VERSION 5.8 ;
BUSBITCHARS "[]" ;
DIVIDERCHAR "/" ;
UNITS
    DATABASE MICRONS 1000 ;
END UNITS

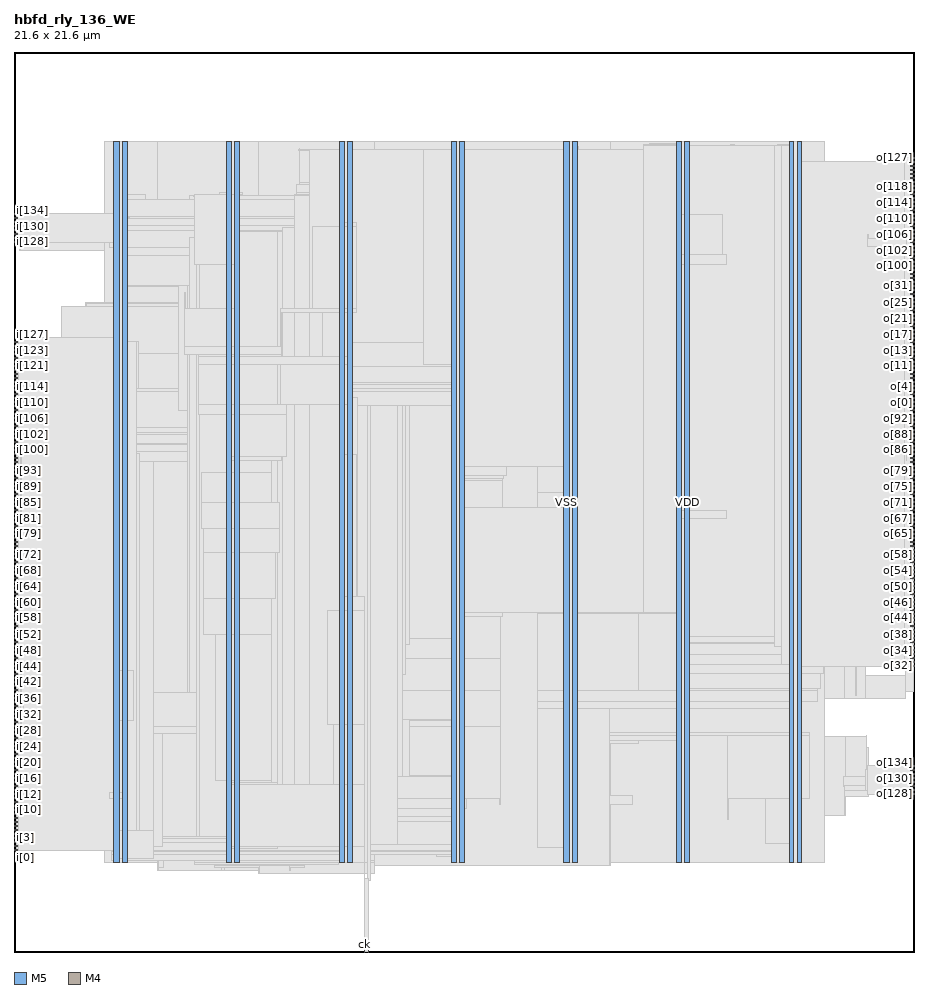
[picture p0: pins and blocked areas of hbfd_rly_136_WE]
MACRO hbfd_rly_136_WE
  FOREIGN hbfd_rly_136_WE 0 0 ;
  CLASS BLOCK ;
  SIZE 21.6 BY 21.6 ;
  PIN ck
    DIRECTION INPUT ;
    USE SIGNAL ;
    PORT
      LAYER M5 ;
        RECT  8.4 0 8.424 0.084 ;
    END
  END ck
  PIN i[0]
    DIRECTION INPUT ;
    USE SIGNAL ;
    PORT
      LAYER M4 ;
        RECT  0 2.448 0.084 2.472 ;
    END
  END i[0]
  PIN i[100]
    DIRECTION INPUT ;
    USE SIGNAL ;
    PORT
      LAYER M4 ;
        RECT  0 12.048 0.084 12.072 ;
    END
  END i[100]
  PIN i[101]
    DIRECTION INPUT ;
    USE SIGNAL ;
    PORT
      LAYER M4 ;
        RECT  0 12.144 0.084 12.168 ;
    END
  END i[101]
  PIN i[102]
    DIRECTION INPUT ;
    USE SIGNAL ;
    PORT
      LAYER M4 ;
        RECT  0 12.24 0.084 12.264 ;
    END
  END i[102]
  PIN i[103]
    DIRECTION INPUT ;
    USE SIGNAL ;
    PORT
      LAYER M4 ;
        RECT  0 12.336 0.084 12.36 ;
    END
  END i[103]
  PIN i[104]
    DIRECTION INPUT ;
    USE SIGNAL ;
    PORT
      LAYER M4 ;
        RECT  0 12.432 0.084 12.456 ;
    END
  END i[104]
  PIN i[105]
    DIRECTION INPUT ;
    USE SIGNAL ;
    PORT
      LAYER M4 ;
        RECT  0 12.528 0.084 12.552 ;
    END
  END i[105]
  PIN i[106]
    DIRECTION INPUT ;
    USE SIGNAL ;
    PORT
      LAYER M4 ;
        RECT  0 12.624 0.084 12.648 ;
    END
  END i[106]
  PIN i[107]
    DIRECTION INPUT ;
    USE SIGNAL ;
    PORT
      LAYER M4 ;
        RECT  0 12.72 0.084 12.744 ;
    END
  END i[107]
  PIN i[108]
    DIRECTION INPUT ;
    USE SIGNAL ;
    PORT
      LAYER M4 ;
        RECT  0 12.816 0.084 12.84 ;
    END
  END i[108]
  PIN i[109]
    DIRECTION INPUT ;
    USE SIGNAL ;
    PORT
      LAYER M4 ;
        RECT  0 12.912 0.084 12.936 ;
    END
  END i[109]
  PIN i[10]
    DIRECTION INPUT ;
    USE SIGNAL ;
    PORT
      LAYER M4 ;
        RECT  0 3.408 0.084 3.432 ;
    END
  END i[10]
  PIN i[110]
    DIRECTION INPUT ;
    USE SIGNAL ;
    PORT
      LAYER M4 ;
        RECT  0 13.008 0.084 13.032 ;
    END
  END i[110]
  PIN i[111]
    DIRECTION INPUT ;
    USE SIGNAL ;
    PORT
      LAYER M4 ;
        RECT  0 13.104 0.084 13.128 ;
    END
  END i[111]
  PIN i[112]
    DIRECTION INPUT ;
    USE SIGNAL ;
    PORT
      LAYER M4 ;
        RECT  0 13.2 0.084 13.224 ;
    END
  END i[112]
  PIN i[113]
    DIRECTION INPUT ;
    USE SIGNAL ;
    PORT
      LAYER M4 ;
        RECT  0 13.296 0.084 13.32 ;
    END
  END i[113]
  PIN i[114]
    DIRECTION INPUT ;
    USE SIGNAL ;
    PORT
      LAYER M4 ;
        RECT  0 13.392 0.084 13.416 ;
    END
  END i[114]
  PIN i[115]
    DIRECTION INPUT ;
    USE SIGNAL ;
    PORT
      LAYER M4 ;
        RECT  0 13.488 0.084 13.512 ;
    END
  END i[115]
  PIN i[116]
    DIRECTION INPUT ;
    USE SIGNAL ;
    PORT
      LAYER M4 ;
        RECT  0 13.584 0.084 13.608 ;
    END
  END i[116]
  PIN i[117]
    DIRECTION INPUT ;
    USE SIGNAL ;
    PORT
      LAYER M4 ;
        RECT  0 13.68 0.084 13.704 ;
    END
  END i[117]
  PIN i[118]
    DIRECTION INPUT ;
    USE SIGNAL ;
    PORT
      LAYER M4 ;
        RECT  0 13.776 0.084 13.8 ;
    END
  END i[118]
  PIN i[119]
    DIRECTION INPUT ;
    USE SIGNAL ;
    PORT
      LAYER M4 ;
        RECT  0 13.872 0.084 13.896 ;
    END
  END i[119]
  PIN i[11]
    DIRECTION INPUT ;
    USE SIGNAL ;
    PORT
      LAYER M4 ;
        RECT  0 3.504 0.084 3.528 ;
    END
  END i[11]
  PIN i[120]
    DIRECTION INPUT ;
    USE SIGNAL ;
    PORT
      LAYER M4 ;
        RECT  0 13.968 0.084 13.992 ;
    END
  END i[120]
  PIN i[121]
    DIRECTION INPUT ;
    USE SIGNAL ;
    PORT
      LAYER M4 ;
        RECT  0 14.064 0.084 14.088 ;
    END
  END i[121]
  PIN i[122]
    DIRECTION INPUT ;
    USE SIGNAL ;
    PORT
      LAYER M4 ;
        RECT  0 14.16 0.084 14.184 ;
    END
  END i[122]
  PIN i[123]
    DIRECTION INPUT ;
    USE SIGNAL ;
    PORT
      LAYER M4 ;
        RECT  0 14.256 0.084 14.28 ;
    END
  END i[123]
  PIN i[124]
    DIRECTION INPUT ;
    USE SIGNAL ;
    PORT
      LAYER M4 ;
        RECT  0 14.352 0.084 14.376 ;
    END
  END i[124]
  PIN i[125]
    DIRECTION INPUT ;
    USE SIGNAL ;
    PORT
      LAYER M4 ;
        RECT  0 14.448 0.084 14.472 ;
    END
  END i[125]
  PIN i[126]
    DIRECTION INPUT ;
    USE SIGNAL ;
    PORT
      LAYER M4 ;
        RECT  0 14.544 0.084 14.568 ;
    END
  END i[126]
  PIN i[127]
    DIRECTION INPUT ;
    USE SIGNAL ;
    PORT
      LAYER M4 ;
        RECT  0 14.64 0.084 14.664 ;
    END
  END i[127]
  PIN i[128]
    DIRECTION INPUT ;
    USE SIGNAL ;
    PORT
      LAYER M4 ;
        RECT  0 17.04 0.084 17.064 ;
    END
  END i[128]
  PIN i[129]
    DIRECTION INPUT ;
    USE SIGNAL ;
    PORT
      LAYER M4 ;
        RECT  0 17.136 0.084 17.16 ;
    END
  END i[129]
  PIN i[12]
    DIRECTION INPUT ;
    USE SIGNAL ;
    PORT
      LAYER M4 ;
        RECT  0 3.6 0.084 3.624 ;
    END
  END i[12]
  PIN i[130]
    DIRECTION INPUT ;
    USE SIGNAL ;
    PORT
      LAYER M4 ;
        RECT  0 17.232 0.084 17.256 ;
    END
  END i[130]
  PIN i[131]
    DIRECTION INPUT ;
    USE SIGNAL ;
    PORT
      LAYER M4 ;
        RECT  0 17.328 0.084 17.352 ;
    END
  END i[131]
  PIN i[132]
    DIRECTION INPUT ;
    USE SIGNAL ;
    PORT
      LAYER M4 ;
        RECT  0 17.424 0.084 17.448 ;
    END
  END i[132]
  PIN i[133]
    DIRECTION INPUT ;
    USE SIGNAL ;
    PORT
      LAYER M4 ;
        RECT  0 17.52 0.084 17.544 ;
    END
  END i[133]
  PIN i[134]
    DIRECTION INPUT ;
    USE SIGNAL ;
    PORT
      LAYER M4 ;
        RECT  0 17.616 0.084 17.64 ;
    END
  END i[134]
  PIN i[135]
    DIRECTION INPUT ;
    USE SIGNAL ;
    PORT
      LAYER M4 ;
        RECT  0 17.712 0.084 17.736 ;
    END
  END i[135]
  PIN i[13]
    DIRECTION INPUT ;
    USE SIGNAL ;
    PORT
      LAYER M4 ;
        RECT  0 3.696 0.084 3.72 ;
    END
  END i[13]
  PIN i[14]
    DIRECTION INPUT ;
    USE SIGNAL ;
    PORT
      LAYER M4 ;
        RECT  0 3.792 0.084 3.816 ;
    END
  END i[14]
  PIN i[15]
    DIRECTION INPUT ;
    USE SIGNAL ;
    PORT
      LAYER M4 ;
        RECT  0 3.888 0.084 3.912 ;
    END
  END i[15]
  PIN i[16]
    DIRECTION INPUT ;
    USE SIGNAL ;
    PORT
      LAYER M4 ;
        RECT  0 3.984 0.084 4.008 ;
    END
  END i[16]
  PIN i[17]
    DIRECTION INPUT ;
    USE SIGNAL ;
    PORT
      LAYER M4 ;
        RECT  0 4.08 0.084 4.104 ;
    END
  END i[17]
  PIN i[18]
    DIRECTION INPUT ;
    USE SIGNAL ;
    PORT
      LAYER M4 ;
        RECT  0 4.176 0.084 4.2 ;
    END
  END i[18]
  PIN i[19]
    DIRECTION INPUT ;
    USE SIGNAL ;
    PORT
      LAYER M4 ;
        RECT  0 4.272 0.084 4.296 ;
    END
  END i[19]
  PIN i[1]
    DIRECTION INPUT ;
    USE SIGNAL ;
    PORT
      LAYER M4 ;
        RECT  0 2.544 0.084 2.568 ;
    END
  END i[1]
  PIN i[20]
    DIRECTION INPUT ;
    USE SIGNAL ;
    PORT
      LAYER M4 ;
        RECT  0 4.368 0.084 4.392 ;
    END
  END i[20]
  PIN i[21]
    DIRECTION INPUT ;
    USE SIGNAL ;
    PORT
      LAYER M4 ;
        RECT  0 4.464 0.084 4.488 ;
    END
  END i[21]
  PIN i[22]
    DIRECTION INPUT ;
    USE SIGNAL ;
    PORT
      LAYER M4 ;
        RECT  0 4.56 0.084 4.584 ;
    END
  END i[22]
  PIN i[23]
    DIRECTION INPUT ;
    USE SIGNAL ;
    PORT
      LAYER M4 ;
        RECT  0 4.656 0.084 4.68 ;
    END
  END i[23]
  PIN i[24]
    DIRECTION INPUT ;
    USE SIGNAL ;
    PORT
      LAYER M4 ;
        RECT  0 4.752 0.084 4.776 ;
    END
  END i[24]
  PIN i[25]
    DIRECTION INPUT ;
    USE SIGNAL ;
    PORT
      LAYER M4 ;
        RECT  0 4.848 0.084 4.872 ;
    END
  END i[25]
  PIN i[26]
    DIRECTION INPUT ;
    USE SIGNAL ;
    PORT
      LAYER M4 ;
        RECT  0 4.944 0.084 4.968 ;
    END
  END i[26]
  PIN i[27]
    DIRECTION INPUT ;
    USE SIGNAL ;
    PORT
      LAYER M4 ;
        RECT  0 5.04 0.084 5.064 ;
    END
  END i[27]
  PIN i[28]
    DIRECTION INPUT ;
    USE SIGNAL ;
    PORT
      LAYER M4 ;
        RECT  0 5.136 0.084 5.16 ;
    END
  END i[28]
  PIN i[29]
    DIRECTION INPUT ;
    USE SIGNAL ;
    PORT
      LAYER M4 ;
        RECT  0 5.232 0.084 5.256 ;
    END
  END i[29]
  PIN i[2]
    DIRECTION INPUT ;
    USE SIGNAL ;
    PORT
      LAYER M4 ;
        RECT  0 2.64 0.084 2.664 ;
    END
  END i[2]
  PIN i[30]
    DIRECTION INPUT ;
    USE SIGNAL ;
    PORT
      LAYER M4 ;
        RECT  0 5.328 0.084 5.352 ;
    END
  END i[30]
  PIN i[31]
    DIRECTION INPUT ;
    USE SIGNAL ;
    PORT
      LAYER M4 ;
        RECT  0 5.424 0.084 5.448 ;
    END
  END i[31]
  PIN i[32]
    DIRECTION INPUT ;
    USE SIGNAL ;
    PORT
      LAYER M4 ;
        RECT  0 5.52 0.084 5.544 ;
    END
  END i[32]
  PIN i[33]
    DIRECTION INPUT ;
    USE SIGNAL ;
    PORT
      LAYER M4 ;
        RECT  0 5.616 0.084 5.64 ;
    END
  END i[33]
  PIN i[34]
    DIRECTION INPUT ;
    USE SIGNAL ;
    PORT
      LAYER M4 ;
        RECT  0 5.712 0.084 5.736 ;
    END
  END i[34]
  PIN i[35]
    DIRECTION INPUT ;
    USE SIGNAL ;
    PORT
      LAYER M4 ;
        RECT  0 5.808 0.084 5.832 ;
    END
  END i[35]
  PIN i[36]
    DIRECTION INPUT ;
    USE SIGNAL ;
    PORT
      LAYER M4 ;
        RECT  0 5.904 0.084 5.928 ;
    END
  END i[36]
  PIN i[37]
    DIRECTION INPUT ;
    USE SIGNAL ;
    PORT
      LAYER M4 ;
        RECT  0 6 0.084 6.024 ;
    END
  END i[37]
  PIN i[38]
    DIRECTION INPUT ;
    USE SIGNAL ;
    PORT
      LAYER M4 ;
        RECT  0 6.096 0.084 6.12 ;
    END
  END i[38]
  PIN i[39]
    DIRECTION INPUT ;
    USE SIGNAL ;
    PORT
      LAYER M4 ;
        RECT  0 6.192 0.084 6.216 ;
    END
  END i[39]
  PIN i[3]
    DIRECTION INPUT ;
    USE SIGNAL ;
    PORT
      LAYER M4 ;
        RECT  0 2.736 0.084 2.76 ;
    END
  END i[3]
  PIN i[40]
    DIRECTION INPUT ;
    USE SIGNAL ;
    PORT
      LAYER M4 ;
        RECT  0 6.288 0.084 6.312 ;
    END
  END i[40]
  PIN i[41]
    DIRECTION INPUT ;
    USE SIGNAL ;
    PORT
      LAYER M4 ;
        RECT  0 6.384 0.084 6.408 ;
    END
  END i[41]
  PIN i[42]
    DIRECTION INPUT ;
    USE SIGNAL ;
    PORT
      LAYER M4 ;
        RECT  0 6.48 0.084 6.504 ;
    END
  END i[42]
  PIN i[43]
    DIRECTION INPUT ;
    USE SIGNAL ;
    PORT
      LAYER M4 ;
        RECT  0 6.576 0.084 6.6 ;
    END
  END i[43]
  PIN i[44]
    DIRECTION INPUT ;
    USE SIGNAL ;
    PORT
      LAYER M4 ;
        RECT  0 6.672 0.084 6.696 ;
    END
  END i[44]
  PIN i[45]
    DIRECTION INPUT ;
    USE SIGNAL ;
    PORT
      LAYER M4 ;
        RECT  0 6.768 0.084 6.792 ;
    END
  END i[45]
  PIN i[46]
    DIRECTION INPUT ;
    USE SIGNAL ;
    PORT
      LAYER M4 ;
        RECT  0 6.864 0.084 6.888 ;
    END
  END i[46]
  PIN i[47]
    DIRECTION INPUT ;
    USE SIGNAL ;
    PORT
      LAYER M4 ;
        RECT  0 6.96 0.084 6.984 ;
    END
  END i[47]
  PIN i[48]
    DIRECTION INPUT ;
    USE SIGNAL ;
    PORT
      LAYER M4 ;
        RECT  0 7.056 0.084 7.08 ;
    END
  END i[48]
  PIN i[49]
    DIRECTION INPUT ;
    USE SIGNAL ;
    PORT
      LAYER M4 ;
        RECT  0 7.152 0.084 7.176 ;
    END
  END i[49]
  PIN i[4]
    DIRECTION INPUT ;
    USE SIGNAL ;
    PORT
      LAYER M4 ;
        RECT  0 2.832 0.084 2.856 ;
    END
  END i[4]
  PIN i[50]
    DIRECTION INPUT ;
    USE SIGNAL ;
    PORT
      LAYER M4 ;
        RECT  0 7.248 0.084 7.272 ;
    END
  END i[50]
  PIN i[51]
    DIRECTION INPUT ;
    USE SIGNAL ;
    PORT
      LAYER M4 ;
        RECT  0 7.344 0.084 7.368 ;
    END
  END i[51]
  PIN i[52]
    DIRECTION INPUT ;
    USE SIGNAL ;
    PORT
      LAYER M4 ;
        RECT  0 7.44 0.084 7.464 ;
    END
  END i[52]
  PIN i[53]
    DIRECTION INPUT ;
    USE SIGNAL ;
    PORT
      LAYER M4 ;
        RECT  0 7.536 0.084 7.56 ;
    END
  END i[53]
  PIN i[54]
    DIRECTION INPUT ;
    USE SIGNAL ;
    PORT
      LAYER M4 ;
        RECT  0 7.632 0.084 7.656 ;
    END
  END i[54]
  PIN i[55]
    DIRECTION INPUT ;
    USE SIGNAL ;
    PORT
      LAYER M4 ;
        RECT  0 7.728 0.084 7.752 ;
    END
  END i[55]
  PIN i[56]
    DIRECTION INPUT ;
    USE SIGNAL ;
    PORT
      LAYER M4 ;
        RECT  0 7.824 0.084 7.848 ;
    END
  END i[56]
  PIN i[57]
    DIRECTION INPUT ;
    USE SIGNAL ;
    PORT
      LAYER M4 ;
        RECT  0 7.92 0.084 7.944 ;
    END
  END i[57]
  PIN i[58]
    DIRECTION INPUT ;
    USE SIGNAL ;
    PORT
      LAYER M4 ;
        RECT  0 8.016 0.084 8.04 ;
    END
  END i[58]
  PIN i[59]
    DIRECTION INPUT ;
    USE SIGNAL ;
    PORT
      LAYER M4 ;
        RECT  0 8.112 0.084 8.136 ;
    END
  END i[59]
  PIN i[5]
    DIRECTION INPUT ;
    USE SIGNAL ;
    PORT
      LAYER M4 ;
        RECT  0 2.928 0.084 2.952 ;
    END
  END i[5]
  PIN i[60]
    DIRECTION INPUT ;
    USE SIGNAL ;
    PORT
      LAYER M4 ;
        RECT  0 8.208 0.084 8.232 ;
    END
  END i[60]
  PIN i[61]
    DIRECTION INPUT ;
    USE SIGNAL ;
    PORT
      LAYER M4 ;
        RECT  0 8.304 0.084 8.328 ;
    END
  END i[61]
  PIN i[62]
    DIRECTION INPUT ;
    USE SIGNAL ;
    PORT
      LAYER M4 ;
        RECT  0 8.4 0.084 8.424 ;
    END
  END i[62]
  PIN i[63]
    DIRECTION INPUT ;
    USE SIGNAL ;
    PORT
      LAYER M4 ;
        RECT  0 8.496 0.084 8.52 ;
    END
  END i[63]
  PIN i[64]
    DIRECTION INPUT ;
    USE SIGNAL ;
    PORT
      LAYER M4 ;
        RECT  0 8.592 0.084 8.616 ;
    END
  END i[64]
  PIN i[65]
    DIRECTION INPUT ;
    USE SIGNAL ;
    PORT
      LAYER M4 ;
        RECT  0 8.688 0.084 8.712 ;
    END
  END i[65]
  PIN i[66]
    DIRECTION INPUT ;
    USE SIGNAL ;
    PORT
      LAYER M4 ;
        RECT  0 8.784 0.084 8.808 ;
    END
  END i[66]
  PIN i[67]
    DIRECTION INPUT ;
    USE SIGNAL ;
    PORT
      LAYER M4 ;
        RECT  0 8.88 0.084 8.904 ;
    END
  END i[67]
  PIN i[68]
    DIRECTION INPUT ;
    USE SIGNAL ;
    PORT
      LAYER M4 ;
        RECT  0 8.976 0.084 9 ;
    END
  END i[68]
  PIN i[69]
    DIRECTION INPUT ;
    USE SIGNAL ;
    PORT
      LAYER M4 ;
        RECT  0 9.072 0.084 9.096 ;
    END
  END i[69]
  PIN i[6]
    DIRECTION INPUT ;
    USE SIGNAL ;
    PORT
      LAYER M4 ;
        RECT  0 3.024 0.084 3.048 ;
    END
  END i[6]
  PIN i[70]
    DIRECTION INPUT ;
    USE SIGNAL ;
    PORT
      LAYER M4 ;
        RECT  0 9.168 0.084 9.192 ;
    END
  END i[70]
  PIN i[71]
    DIRECTION INPUT ;
    USE SIGNAL ;
    PORT
      LAYER M4 ;
        RECT  0 9.264 0.084 9.288 ;
    END
  END i[71]
  PIN i[72]
    DIRECTION INPUT ;
    USE SIGNAL ;
    PORT
      LAYER M4 ;
        RECT  0 9.36 0.084 9.384 ;
    END
  END i[72]
  PIN i[73]
    DIRECTION INPUT ;
    USE SIGNAL ;
    PORT
      LAYER M4 ;
        RECT  0 9.456 0.084 9.48 ;
    END
  END i[73]
  PIN i[74]
    DIRECTION INPUT ;
    USE SIGNAL ;
    PORT
      LAYER M4 ;
        RECT  0 9.552 0.084 9.576 ;
    END
  END i[74]
  PIN i[75]
    DIRECTION INPUT ;
    USE SIGNAL ;
    PORT
      LAYER M4 ;
        RECT  0 9.648 0.084 9.672 ;
    END
  END i[75]
  PIN i[76]
    DIRECTION INPUT ;
    USE SIGNAL ;
    PORT
      LAYER M4 ;
        RECT  0 9.744 0.084 9.768 ;
    END
  END i[76]
  PIN i[77]
    DIRECTION INPUT ;
    USE SIGNAL ;
    PORT
      LAYER M4 ;
        RECT  0 9.84 0.084 9.864 ;
    END
  END i[77]
  PIN i[78]
    DIRECTION INPUT ;
    USE SIGNAL ;
    PORT
      LAYER M4 ;
        RECT  0 9.936 0.084 9.96 ;
    END
  END i[78]
  PIN i[79]
    DIRECTION INPUT ;
    USE SIGNAL ;
    PORT
      LAYER M4 ;
        RECT  0 10.032 0.084 10.056 ;
    END
  END i[79]
  PIN i[7]
    DIRECTION INPUT ;
    USE SIGNAL ;
    PORT
      LAYER M4 ;
        RECT  0 3.12 0.084 3.144 ;
    END
  END i[7]
  PIN i[80]
    DIRECTION INPUT ;
    USE SIGNAL ;
    PORT
      LAYER M4 ;
        RECT  0 10.128 0.084 10.152 ;
    END
  END i[80]
  PIN i[81]
    DIRECTION INPUT ;
    USE SIGNAL ;
    PORT
      LAYER M4 ;
        RECT  0 10.224 0.084 10.248 ;
    END
  END i[81]
  PIN i[82]
    DIRECTION INPUT ;
    USE SIGNAL ;
    PORT
      LAYER M4 ;
        RECT  0 10.32 0.084 10.344 ;
    END
  END i[82]
  PIN i[83]
    DIRECTION INPUT ;
    USE SIGNAL ;
    PORT
      LAYER M4 ;
        RECT  0 10.416 0.084 10.44 ;
    END
  END i[83]
  PIN i[84]
    DIRECTION INPUT ;
    USE SIGNAL ;
    PORT
      LAYER M4 ;
        RECT  0 10.512 0.084 10.536 ;
    END
  END i[84]
  PIN i[85]
    DIRECTION INPUT ;
    USE SIGNAL ;
    PORT
      LAYER M4 ;
        RECT  0 10.608 0.084 10.632 ;
    END
  END i[85]
  PIN i[86]
    DIRECTION INPUT ;
    USE SIGNAL ;
    PORT
      LAYER M4 ;
        RECT  0 10.704 0.084 10.728 ;
    END
  END i[86]
  PIN i[87]
    DIRECTION INPUT ;
    USE SIGNAL ;
    PORT
      LAYER M4 ;
        RECT  0 10.8 0.084 10.824 ;
    END
  END i[87]
  PIN i[88]
    DIRECTION INPUT ;
    USE SIGNAL ;
    PORT
      LAYER M4 ;
        RECT  0 10.896 0.084 10.92 ;
    END
  END i[88]
  PIN i[89]
    DIRECTION INPUT ;
    USE SIGNAL ;
    PORT
      LAYER M4 ;
        RECT  0 10.992 0.084 11.016 ;
    END
  END i[89]
  PIN i[8]
    DIRECTION INPUT ;
    USE SIGNAL ;
    PORT
      LAYER M4 ;
        RECT  0 3.216 0.084 3.24 ;
    END
  END i[8]
  PIN i[90]
    DIRECTION INPUT ;
    USE SIGNAL ;
    PORT
      LAYER M4 ;
        RECT  0 11.088 0.084 11.112 ;
    END
  END i[90]
  PIN i[91]
    DIRECTION INPUT ;
    USE SIGNAL ;
    PORT
      LAYER M4 ;
        RECT  0 11.184 0.084 11.208 ;
    END
  END i[91]
  PIN i[92]
    DIRECTION INPUT ;
    USE SIGNAL ;
    PORT
      LAYER M4 ;
        RECT  0 11.28 0.084 11.304 ;
    END
  END i[92]
  PIN i[93]
    DIRECTION INPUT ;
    USE SIGNAL ;
    PORT
      LAYER M4 ;
        RECT  0 11.376 0.084 11.4 ;
    END
  END i[93]
  PIN i[94]
    DIRECTION INPUT ;
    USE SIGNAL ;
    PORT
      LAYER M4 ;
        RECT  0 11.472 0.084 11.496 ;
    END
  END i[94]
  PIN i[95]
    DIRECTION INPUT ;
    USE SIGNAL ;
    PORT
      LAYER M4 ;
        RECT  0 11.568 0.084 11.592 ;
    END
  END i[95]
  PIN i[96]
    DIRECTION INPUT ;
    USE SIGNAL ;
    PORT
      LAYER M4 ;
        RECT  0 11.664 0.084 11.688 ;
    END
  END i[96]
  PIN i[97]
    DIRECTION INPUT ;
    USE SIGNAL ;
    PORT
      LAYER M4 ;
        RECT  0 11.76 0.084 11.784 ;
    END
  END i[97]
  PIN i[98]
    DIRECTION INPUT ;
    USE SIGNAL ;
    PORT
      LAYER M4 ;
        RECT  0 11.856 0.084 11.88 ;
    END
  END i[98]
  PIN i[99]
    DIRECTION INPUT ;
    USE SIGNAL ;
    PORT
      LAYER M4 ;
        RECT  0 11.952 0.084 11.976 ;
    END
  END i[99]
  PIN i[9]
    DIRECTION INPUT ;
    USE SIGNAL ;
    PORT
      LAYER M4 ;
        RECT  0 3.312 0.084 3.336 ;
    END
  END i[9]
  PIN o[0]
    DIRECTION OUTPUT ;
    USE SIGNAL ;
    PORT
      LAYER M4 ;
        RECT  21.516 13.008 21.6 13.032 ;
    END
  END o[0]
  PIN o[100]
    DIRECTION OUTPUT ;
    USE SIGNAL ;
    PORT
      LAYER M4 ;
        RECT  21.516 16.464 21.6 16.488 ;
    END
  END o[100]
  PIN o[101]
    DIRECTION OUTPUT ;
    USE SIGNAL ;
    PORT
      LAYER M4 ;
        RECT  21.516 16.56 21.6 16.584 ;
    END
  END o[101]
  PIN o[102]
    DIRECTION OUTPUT ;
    USE SIGNAL ;
    PORT
      LAYER M4 ;
        RECT  21.516 16.656 21.6 16.68 ;
    END
  END o[102]
  PIN o[103]
    DIRECTION OUTPUT ;
    USE SIGNAL ;
    PORT
      LAYER M4 ;
        RECT  21.516 16.752 21.6 16.776 ;
    END
  END o[103]
  PIN o[104]
    DIRECTION OUTPUT ;
    USE SIGNAL ;
    PORT
      LAYER M4 ;
        RECT  21.516 16.848 21.6 16.872 ;
    END
  END o[104]
  PIN o[105]
    DIRECTION OUTPUT ;
    USE SIGNAL ;
    PORT
      LAYER M4 ;
        RECT  21.516 16.944 21.6 16.968 ;
    END
  END o[105]
  PIN o[106]
    DIRECTION OUTPUT ;
    USE SIGNAL ;
    PORT
      LAYER M4 ;
        RECT  21.516 17.04 21.6 17.064 ;
    END
  END o[106]
  PIN o[107]
    DIRECTION OUTPUT ;
    USE SIGNAL ;
    PORT
      LAYER M4 ;
        RECT  21.516 17.136 21.6 17.16 ;
    END
  END o[107]
  PIN o[108]
    DIRECTION OUTPUT ;
    USE SIGNAL ;
    PORT
      LAYER M4 ;
        RECT  21.516 17.232 21.6 17.256 ;
    END
  END o[108]
  PIN o[109]
    DIRECTION OUTPUT ;
    USE SIGNAL ;
    PORT
      LAYER M4 ;
        RECT  21.516 17.328 21.6 17.352 ;
    END
  END o[109]
  PIN o[10]
    DIRECTION OUTPUT ;
    USE SIGNAL ;
    PORT
      LAYER M4 ;
        RECT  21.516 13.968 21.6 13.992 ;
    END
  END o[10]
  PIN o[110]
    DIRECTION OUTPUT ;
    USE SIGNAL ;
    PORT
      LAYER M4 ;
        RECT  21.516 17.424 21.6 17.448 ;
    END
  END o[110]
  PIN o[111]
    DIRECTION OUTPUT ;
    USE SIGNAL ;
    PORT
      LAYER M4 ;
        RECT  21.516 17.52 21.6 17.544 ;
    END
  END o[111]
  PIN o[112]
    DIRECTION OUTPUT ;
    USE SIGNAL ;
    PORT
      LAYER M4 ;
        RECT  21.516 17.616 21.6 17.64 ;
    END
  END o[112]
  PIN o[113]
    DIRECTION OUTPUT ;
    USE SIGNAL ;
    PORT
      LAYER M4 ;
        RECT  21.516 17.712 21.6 17.736 ;
    END
  END o[113]
  PIN o[114]
    DIRECTION OUTPUT ;
    USE SIGNAL ;
    PORT
      LAYER M4 ;
        RECT  21.516 17.808 21.6 17.832 ;
    END
  END o[114]
  PIN o[115]
    DIRECTION OUTPUT ;
    USE SIGNAL ;
    PORT
      LAYER M4 ;
        RECT  21.516 17.904 21.6 17.928 ;
    END
  END o[115]
  PIN o[116]
    DIRECTION OUTPUT ;
    USE SIGNAL ;
    PORT
      LAYER M4 ;
        RECT  21.516 18 21.6 18.024 ;
    END
  END o[116]
  PIN o[117]
    DIRECTION OUTPUT ;
    USE SIGNAL ;
    PORT
      LAYER M4 ;
        RECT  21.516 18.096 21.6 18.12 ;
    END
  END o[117]
  PIN o[118]
    DIRECTION OUTPUT ;
    USE SIGNAL ;
    PORT
      LAYER M4 ;
        RECT  21.516 18.192 21.6 18.216 ;
    END
  END o[118]
  PIN o[119]
    DIRECTION OUTPUT ;
    USE SIGNAL ;
    PORT
      LAYER M4 ;
        RECT  21.516 18.288 21.6 18.312 ;
    END
  END o[119]
  PIN o[11]
    DIRECTION OUTPUT ;
    USE SIGNAL ;
    PORT
      LAYER M4 ;
        RECT  21.516 14.064 21.6 14.088 ;
    END
  END o[11]
  PIN o[120]
    DIRECTION OUTPUT ;
    USE SIGNAL ;
    PORT
      LAYER M4 ;
        RECT  21.516 18.384 21.6 18.408 ;
    END
  END o[120]
  PIN o[121]
    DIRECTION OUTPUT ;
    USE SIGNAL ;
    PORT
      LAYER M4 ;
        RECT  21.516 18.48 21.6 18.504 ;
    END
  END o[121]
  PIN o[122]
    DIRECTION OUTPUT ;
    USE SIGNAL ;
    PORT
      LAYER M4 ;
        RECT  21.516 18.576 21.6 18.6 ;
    END
  END o[122]
  PIN o[123]
    DIRECTION OUTPUT ;
    USE SIGNAL ;
    PORT
      LAYER M4 ;
        RECT  21.516 18.672 21.6 18.696 ;
    END
  END o[123]
  PIN o[124]
    DIRECTION OUTPUT ;
    USE SIGNAL ;
    PORT
      LAYER M4 ;
        RECT  21.516 18.768 21.6 18.792 ;
    END
  END o[124]
  PIN o[125]
    DIRECTION OUTPUT ;
    USE SIGNAL ;
    PORT
      LAYER M4 ;
        RECT  21.516 18.864 21.6 18.888 ;
    END
  END o[125]
  PIN o[126]
    DIRECTION OUTPUT ;
    USE SIGNAL ;
    PORT
      LAYER M4 ;
        RECT  21.516 18.96 21.6 18.984 ;
    END
  END o[126]
  PIN o[127]
    DIRECTION OUTPUT ;
    USE SIGNAL ;
    PORT
      LAYER M4 ;
        RECT  21.516 19.056 21.6 19.08 ;
    END
  END o[127]
  PIN o[128]
    DIRECTION OUTPUT ;
    USE SIGNAL ;
    PORT
      LAYER M4 ;
        RECT  21.516 3.792 21.6 3.816 ;
    END
  END o[128]
  PIN o[129]
    DIRECTION OUTPUT ;
    USE SIGNAL ;
    PORT
      LAYER M4 ;
        RECT  21.516 3.888 21.6 3.912 ;
    END
  END o[129]
  PIN o[12]
    DIRECTION OUTPUT ;
    USE SIGNAL ;
    PORT
      LAYER M4 ;
        RECT  21.516 14.16 21.6 14.184 ;
    END
  END o[12]
  PIN o[130]
    DIRECTION OUTPUT ;
    USE SIGNAL ;
    PORT
      LAYER M4 ;
        RECT  21.516 3.984 21.6 4.008 ;
    END
  END o[130]
  PIN o[131]
    DIRECTION OUTPUT ;
    USE SIGNAL ;
    PORT
      LAYER M4 ;
        RECT  21.516 4.08 21.6 4.104 ;
    END
  END o[131]
  PIN o[132]
    DIRECTION OUTPUT ;
    USE SIGNAL ;
    PORT
      LAYER M4 ;
        RECT  21.516 4.176 21.6 4.2 ;
    END
  END o[132]
  PIN o[133]
    DIRECTION OUTPUT ;
    USE SIGNAL ;
    PORT
      LAYER M4 ;
        RECT  21.516 4.272 21.6 4.296 ;
    END
  END o[133]
  PIN o[134]
    DIRECTION OUTPUT ;
    USE SIGNAL ;
    PORT
      LAYER M4 ;
        RECT  21.516 4.368 21.6 4.392 ;
    END
  END o[134]
  PIN o[135]
    DIRECTION OUTPUT ;
    USE SIGNAL ;
    PORT
      LAYER M4 ;
        RECT  21.516 4.464 21.6 4.488 ;
    END
  END o[135]
  PIN o[13]
    DIRECTION OUTPUT ;
    USE SIGNAL ;
    PORT
      LAYER M4 ;
        RECT  21.516 14.256 21.6 14.28 ;
    END
  END o[13]
  PIN o[14]
    DIRECTION OUTPUT ;
    USE SIGNAL ;
    PORT
      LAYER M4 ;
        RECT  21.516 14.352 21.6 14.376 ;
    END
  END o[14]
  PIN o[15]
    DIRECTION OUTPUT ;
    USE SIGNAL ;
    PORT
      LAYER M4 ;
        RECT  21.516 14.448 21.6 14.472 ;
    END
  END o[15]
  PIN o[16]
    DIRECTION OUTPUT ;
    USE SIGNAL ;
    PORT
      LAYER M4 ;
        RECT  21.516 14.544 21.6 14.568 ;
    END
  END o[16]
  PIN o[17]
    DIRECTION OUTPUT ;
    USE SIGNAL ;
    PORT
      LAYER M4 ;
        RECT  21.516 14.64 21.6 14.664 ;
    END
  END o[17]
  PIN o[18]
    DIRECTION OUTPUT ;
    USE SIGNAL ;
    PORT
      LAYER M4 ;
        RECT  21.516 14.736 21.6 14.76 ;
    END
  END o[18]
  PIN o[19]
    DIRECTION OUTPUT ;
    USE SIGNAL ;
    PORT
      LAYER M4 ;
        RECT  21.516 14.832 21.6 14.856 ;
    END
  END o[19]
  PIN o[1]
    DIRECTION OUTPUT ;
    USE SIGNAL ;
    PORT
      LAYER M4 ;
        RECT  21.516 13.104 21.6 13.128 ;
    END
  END o[1]
  PIN o[20]
    DIRECTION OUTPUT ;
    USE SIGNAL ;
    PORT
      LAYER M4 ;
        RECT  21.516 14.928 21.6 14.952 ;
    END
  END o[20]
  PIN o[21]
    DIRECTION OUTPUT ;
    USE SIGNAL ;
    PORT
      LAYER M4 ;
        RECT  21.516 15.024 21.6 15.048 ;
    END
  END o[21]
  PIN o[22]
    DIRECTION OUTPUT ;
    USE SIGNAL ;
    PORT
      LAYER M4 ;
        RECT  21.516 15.12 21.6 15.144 ;
    END
  END o[22]
  PIN o[23]
    DIRECTION OUTPUT ;
    USE SIGNAL ;
    PORT
      LAYER M4 ;
        RECT  21.516 15.216 21.6 15.24 ;
    END
  END o[23]
  PIN o[24]
    DIRECTION OUTPUT ;
    USE SIGNAL ;
    PORT
      LAYER M4 ;
        RECT  21.516 15.312 21.6 15.336 ;
    END
  END o[24]
  PIN o[25]
    DIRECTION OUTPUT ;
    USE SIGNAL ;
    PORT
      LAYER M4 ;
        RECT  21.516 15.408 21.6 15.432 ;
    END
  END o[25]
  PIN o[26]
    DIRECTION OUTPUT ;
    USE SIGNAL ;
    PORT
      LAYER M4 ;
        RECT  21.516 15.504 21.6 15.528 ;
    END
  END o[26]
  PIN o[27]
    DIRECTION OUTPUT ;
    USE SIGNAL ;
    PORT
      LAYER M4 ;
        RECT  21.516 15.6 21.6 15.624 ;
    END
  END o[27]
  PIN o[28]
    DIRECTION OUTPUT ;
    USE SIGNAL ;
    PORT
      LAYER M4 ;
        RECT  21.516 15.696 21.6 15.72 ;
    END
  END o[28]
  PIN o[29]
    DIRECTION OUTPUT ;
    USE SIGNAL ;
    PORT
      LAYER M4 ;
        RECT  21.516 15.792 21.6 15.816 ;
    END
  END o[29]
  PIN o[2]
    DIRECTION OUTPUT ;
    USE SIGNAL ;
    PORT
      LAYER M4 ;
        RECT  21.516 13.2 21.6 13.224 ;
    END
  END o[2]
  PIN o[30]
    DIRECTION OUTPUT ;
    USE SIGNAL ;
    PORT
      LAYER M4 ;
        RECT  21.516 15.888 21.6 15.912 ;
    END
  END o[30]
  PIN o[31]
    DIRECTION OUTPUT ;
    USE SIGNAL ;
    PORT
      LAYER M4 ;
        RECT  21.516 15.984 21.6 16.008 ;
    END
  END o[31]
  PIN o[32]
    DIRECTION OUTPUT ;
    USE SIGNAL ;
    PORT
      LAYER M4 ;
        RECT  21.516 6.864 21.6 6.888 ;
    END
  END o[32]
  PIN o[33]
    DIRECTION OUTPUT ;
    USE SIGNAL ;
    PORT
      LAYER M4 ;
        RECT  21.516 6.96 21.6 6.984 ;
    END
  END o[33]
  PIN o[34]
    DIRECTION OUTPUT ;
    USE SIGNAL ;
    PORT
      LAYER M4 ;
        RECT  21.516 7.056 21.6 7.08 ;
    END
  END o[34]
  PIN o[35]
    DIRECTION OUTPUT ;
    USE SIGNAL ;
    PORT
      LAYER M4 ;
        RECT  21.516 7.152 21.6 7.176 ;
    END
  END o[35]
  PIN o[36]
    DIRECTION OUTPUT ;
    USE SIGNAL ;
    PORT
      LAYER M4 ;
        RECT  21.516 7.248 21.6 7.272 ;
    END
  END o[36]
  PIN o[37]
    DIRECTION OUTPUT ;
    USE SIGNAL ;
    PORT
      LAYER M4 ;
        RECT  21.516 7.344 21.6 7.368 ;
    END
  END o[37]
  PIN o[38]
    DIRECTION OUTPUT ;
    USE SIGNAL ;
    PORT
      LAYER M4 ;
        RECT  21.516 7.44 21.6 7.464 ;
    END
  END o[38]
  PIN o[39]
    DIRECTION OUTPUT ;
    USE SIGNAL ;
    PORT
      LAYER M4 ;
        RECT  21.516 7.536 21.6 7.56 ;
    END
  END o[39]
  PIN o[3]
    DIRECTION OUTPUT ;
    USE SIGNAL ;
    PORT
      LAYER M4 ;
        RECT  21.516 13.296 21.6 13.32 ;
    END
  END o[3]
  PIN o[40]
    DIRECTION OUTPUT ;
    USE SIGNAL ;
    PORT
      LAYER M4 ;
        RECT  21.516 7.632 21.6 7.656 ;
    END
  END o[40]
  PIN o[41]
    DIRECTION OUTPUT ;
    USE SIGNAL ;
    PORT
      LAYER M4 ;
        RECT  21.516 7.728 21.6 7.752 ;
    END
  END o[41]
  PIN o[42]
    DIRECTION OUTPUT ;
    USE SIGNAL ;
    PORT
      LAYER M4 ;
        RECT  21.516 7.824 21.6 7.848 ;
    END
  END o[42]
  PIN o[43]
    DIRECTION OUTPUT ;
    USE SIGNAL ;
    PORT
      LAYER M4 ;
        RECT  21.516 7.92 21.6 7.944 ;
    END
  END o[43]
  PIN o[44]
    DIRECTION OUTPUT ;
    USE SIGNAL ;
    PORT
      LAYER M4 ;
        RECT  21.516 8.016 21.6 8.04 ;
    END
  END o[44]
  PIN o[45]
    DIRECTION OUTPUT ;
    USE SIGNAL ;
    PORT
      LAYER M4 ;
        RECT  21.516 8.112 21.6 8.136 ;
    END
  END o[45]
  PIN o[46]
    DIRECTION OUTPUT ;
    USE SIGNAL ;
    PORT
      LAYER M4 ;
        RECT  21.516 8.208 21.6 8.232 ;
    END
  END o[46]
  PIN o[47]
    DIRECTION OUTPUT ;
    USE SIGNAL ;
    PORT
      LAYER M4 ;
        RECT  21.516 8.304 21.6 8.328 ;
    END
  END o[47]
  PIN o[48]
    DIRECTION OUTPUT ;
    USE SIGNAL ;
    PORT
      LAYER M4 ;
        RECT  21.516 8.4 21.6 8.424 ;
    END
  END o[48]
  PIN o[49]
    DIRECTION OUTPUT ;
    USE SIGNAL ;
    PORT
      LAYER M4 ;
        RECT  21.516 8.496 21.6 8.52 ;
    END
  END o[49]
  PIN o[4]
    DIRECTION OUTPUT ;
    USE SIGNAL ;
    PORT
      LAYER M4 ;
        RECT  21.516 13.392 21.6 13.416 ;
    END
  END o[4]
  PIN o[50]
    DIRECTION OUTPUT ;
    USE SIGNAL ;
    PORT
      LAYER M4 ;
        RECT  21.516 8.592 21.6 8.616 ;
    END
  END o[50]
  PIN o[51]
    DIRECTION OUTPUT ;
    USE SIGNAL ;
    PORT
      LAYER M4 ;
        RECT  21.516 8.688 21.6 8.712 ;
    END
  END o[51]
  PIN o[52]
    DIRECTION OUTPUT ;
    USE SIGNAL ;
    PORT
      LAYER M4 ;
        RECT  21.516 8.784 21.6 8.808 ;
    END
  END o[52]
  PIN o[53]
    DIRECTION OUTPUT ;
    USE SIGNAL ;
    PORT
      LAYER M4 ;
        RECT  21.516 8.88 21.6 8.904 ;
    END
  END o[53]
  PIN o[54]
    DIRECTION OUTPUT ;
    USE SIGNAL ;
    PORT
      LAYER M4 ;
        RECT  21.516 8.976 21.6 9 ;
    END
  END o[54]
  PIN o[55]
    DIRECTION OUTPUT ;
    USE SIGNAL ;
    PORT
      LAYER M4 ;
        RECT  21.516 9.072 21.6 9.096 ;
    END
  END o[55]
  PIN o[56]
    DIRECTION OUTPUT ;
    USE SIGNAL ;
    PORT
      LAYER M4 ;
        RECT  21.516 9.168 21.6 9.192 ;
    END
  END o[56]
  PIN o[57]
    DIRECTION OUTPUT ;
    USE SIGNAL ;
    PORT
      LAYER M4 ;
        RECT  21.516 9.264 21.6 9.288 ;
    END
  END o[57]
  PIN o[58]
    DIRECTION OUTPUT ;
    USE SIGNAL ;
    PORT
      LAYER M4 ;
        RECT  21.516 9.36 21.6 9.384 ;
    END
  END o[58]
  PIN o[59]
    DIRECTION OUTPUT ;
    USE SIGNAL ;
    PORT
      LAYER M4 ;
        RECT  21.516 9.456 21.6 9.48 ;
    END
  END o[59]
  PIN o[5]
    DIRECTION OUTPUT ;
    USE SIGNAL ;
    PORT
      LAYER M4 ;
        RECT  21.516 13.488 21.6 13.512 ;
    END
  END o[5]
  PIN o[60]
    DIRECTION OUTPUT ;
    USE SIGNAL ;
    PORT
      LAYER M4 ;
        RECT  21.516 9.552 21.6 9.576 ;
    END
  END o[60]
  PIN o[61]
    DIRECTION OUTPUT ;
    USE SIGNAL ;
    PORT
      LAYER M4 ;
        RECT  21.516 9.648 21.6 9.672 ;
    END
  END o[61]
  PIN o[62]
    DIRECTION OUTPUT ;
    USE SIGNAL ;
    PORT
      LAYER M4 ;
        RECT  21.516 9.744 21.6 9.768 ;
    END
  END o[62]
  PIN o[63]
    DIRECTION OUTPUT ;
    USE SIGNAL ;
    PORT
      LAYER M4 ;
        RECT  21.516 9.84 21.6 9.864 ;
    END
  END o[63]
  PIN o[64]
    DIRECTION OUTPUT ;
    USE SIGNAL ;
    PORT
      LAYER M4 ;
        RECT  21.516 9.936 21.6 9.96 ;
    END
  END o[64]
  PIN o[65]
    DIRECTION OUTPUT ;
    USE SIGNAL ;
    PORT
      LAYER M4 ;
        RECT  21.516 10.032 21.6 10.056 ;
    END
  END o[65]
  PIN o[66]
    DIRECTION OUTPUT ;
    USE SIGNAL ;
    PORT
      LAYER M4 ;
        RECT  21.516 10.128 21.6 10.152 ;
    END
  END o[66]
  PIN o[67]
    DIRECTION OUTPUT ;
    USE SIGNAL ;
    PORT
      LAYER M4 ;
        RECT  21.516 10.224 21.6 10.248 ;
    END
  END o[67]
  PIN o[68]
    DIRECTION OUTPUT ;
    USE SIGNAL ;
    PORT
      LAYER M4 ;
        RECT  21.516 10.32 21.6 10.344 ;
    END
  END o[68]
  PIN o[69]
    DIRECTION OUTPUT ;
    USE SIGNAL ;
    PORT
      LAYER M4 ;
        RECT  21.516 10.416 21.6 10.44 ;
    END
  END o[69]
  PIN o[6]
    DIRECTION OUTPUT ;
    USE SIGNAL ;
    PORT
      LAYER M4 ;
        RECT  21.516 13.584 21.6 13.608 ;
    END
  END o[6]
  PIN o[70]
    DIRECTION OUTPUT ;
    USE SIGNAL ;
    PORT
      LAYER M4 ;
        RECT  21.516 10.512 21.6 10.536 ;
    END
  END o[70]
  PIN o[71]
    DIRECTION OUTPUT ;
    USE SIGNAL ;
    PORT
      LAYER M4 ;
        RECT  21.516 10.608 21.6 10.632 ;
    END
  END o[71]
  PIN o[72]
    DIRECTION OUTPUT ;
    USE SIGNAL ;
    PORT
      LAYER M4 ;
        RECT  21.516 10.704 21.6 10.728 ;
    END
  END o[72]
  PIN o[73]
    DIRECTION OUTPUT ;
    USE SIGNAL ;
    PORT
      LAYER M4 ;
        RECT  21.516 10.8 21.6 10.824 ;
    END
  END o[73]
  PIN o[74]
    DIRECTION OUTPUT ;
    USE SIGNAL ;
    PORT
      LAYER M4 ;
        RECT  21.516 10.896 21.6 10.92 ;
    END
  END o[74]
  PIN o[75]
    DIRECTION OUTPUT ;
    USE SIGNAL ;
    PORT
      LAYER M4 ;
        RECT  21.516 10.992 21.6 11.016 ;
    END
  END o[75]
  PIN o[76]
    DIRECTION OUTPUT ;
    USE SIGNAL ;
    PORT
      LAYER M4 ;
        RECT  21.516 11.088 21.6 11.112 ;
    END
  END o[76]
  PIN o[77]
    DIRECTION OUTPUT ;
    USE SIGNAL ;
    PORT
      LAYER M4 ;
        RECT  21.516 11.184 21.6 11.208 ;
    END
  END o[77]
  PIN o[78]
    DIRECTION OUTPUT ;
    USE SIGNAL ;
    PORT
      LAYER M4 ;
        RECT  21.516 11.28 21.6 11.304 ;
    END
  END o[78]
  PIN o[79]
    DIRECTION OUTPUT ;
    USE SIGNAL ;
    PORT
      LAYER M4 ;
        RECT  21.516 11.376 21.6 11.4 ;
    END
  END o[79]
  PIN o[7]
    DIRECTION OUTPUT ;
    USE SIGNAL ;
    PORT
      LAYER M4 ;
        RECT  21.516 13.68 21.6 13.704 ;
    END
  END o[7]
  PIN o[80]
    DIRECTION OUTPUT ;
    USE SIGNAL ;
    PORT
      LAYER M4 ;
        RECT  21.516 11.472 21.6 11.496 ;
    END
  END o[80]
  PIN o[81]
    DIRECTION OUTPUT ;
    USE SIGNAL ;
    PORT
      LAYER M4 ;
        RECT  21.516 11.568 21.6 11.592 ;
    END
  END o[81]
  PIN o[82]
    DIRECTION OUTPUT ;
    USE SIGNAL ;
    PORT
      LAYER M4 ;
        RECT  21.516 11.664 21.6 11.688 ;
    END
  END o[82]
  PIN o[83]
    DIRECTION OUTPUT ;
    USE SIGNAL ;
    PORT
      LAYER M4 ;
        RECT  21.516 11.76 21.6 11.784 ;
    END
  END o[83]
  PIN o[84]
    DIRECTION OUTPUT ;
    USE SIGNAL ;
    PORT
      LAYER M4 ;
        RECT  21.516 11.856 21.6 11.88 ;
    END
  END o[84]
  PIN o[85]
    DIRECTION OUTPUT ;
    USE SIGNAL ;
    PORT
      LAYER M4 ;
        RECT  21.516 11.952 21.6 11.976 ;
    END
  END o[85]
  PIN o[86]
    DIRECTION OUTPUT ;
    USE SIGNAL ;
    PORT
      LAYER M4 ;
        RECT  21.516 12.048 21.6 12.072 ;
    END
  END o[86]
  PIN o[87]
    DIRECTION OUTPUT ;
    USE SIGNAL ;
    PORT
      LAYER M4 ;
        RECT  21.516 12.144 21.6 12.168 ;
    END
  END o[87]
  PIN o[88]
    DIRECTION OUTPUT ;
    USE SIGNAL ;
    PORT
      LAYER M4 ;
        RECT  21.516 12.24 21.6 12.264 ;
    END
  END o[88]
  PIN o[89]
    DIRECTION OUTPUT ;
    USE SIGNAL ;
    PORT
      LAYER M4 ;
        RECT  21.516 12.336 21.6 12.36 ;
    END
  END o[89]
  PIN o[8]
    DIRECTION OUTPUT ;
    USE SIGNAL ;
    PORT
      LAYER M4 ;
        RECT  21.516 13.776 21.6 13.8 ;
    END
  END o[8]
  PIN o[90]
    DIRECTION OUTPUT ;
    USE SIGNAL ;
    PORT
      LAYER M4 ;
        RECT  21.516 12.432 21.6 12.456 ;
    END
  END o[90]
  PIN o[91]
    DIRECTION OUTPUT ;
    USE SIGNAL ;
    PORT
      LAYER M4 ;
        RECT  21.516 12.528 21.6 12.552 ;
    END
  END o[91]
  PIN o[92]
    DIRECTION OUTPUT ;
    USE SIGNAL ;
    PORT
      LAYER M4 ;
        RECT  21.516 12.624 21.6 12.648 ;
    END
  END o[92]
  PIN o[93]
    DIRECTION OUTPUT ;
    USE SIGNAL ;
    PORT
      LAYER M4 ;
        RECT  21.516 12.72 21.6 12.744 ;
    END
  END o[93]
  PIN o[94]
    DIRECTION OUTPUT ;
    USE SIGNAL ;
    PORT
      LAYER M4 ;
        RECT  21.516 12.816 21.6 12.84 ;
    END
  END o[94]
  PIN o[95]
    DIRECTION OUTPUT ;
    USE SIGNAL ;
    PORT
      LAYER M4 ;
        RECT  21.516 12.912 21.6 12.936 ;
    END
  END o[95]
  PIN o[96]
    DIRECTION OUTPUT ;
    USE SIGNAL ;
    PORT
      LAYER M4 ;
        RECT  21.516 16.08 21.6 16.104 ;
    END
  END o[96]
  PIN o[97]
    DIRECTION OUTPUT ;
    USE SIGNAL ;
    PORT
      LAYER M4 ;
        RECT  21.516 16.176 21.6 16.2 ;
    END
  END o[97]
  PIN o[98]
    DIRECTION OUTPUT ;
    USE SIGNAL ;
    PORT
      LAYER M4 ;
        RECT  21.516 16.272 21.6 16.296 ;
    END
  END o[98]
  PIN o[99]
    DIRECTION OUTPUT ;
    USE SIGNAL ;
    PORT
      LAYER M4 ;
        RECT  21.516 16.368 21.6 16.392 ;
    END
  END o[99]
  PIN o[9]
    DIRECTION OUTPUT ;
    USE SIGNAL ;
    PORT
      LAYER M4 ;
        RECT  21.516 13.872 21.6 13.896 ;
    END
  END o[9]
  PIN rs
    DIRECTION INPUT ;
    USE SIGNAL ;
    PORT
      LAYER M5 ;
        RECT  8.496 0 8.52 0.084 ;
    END
  END rs
  PIN VDD
    DIRECTION INOUT ;
    USE POWER ;
    PORT
      LAYER M5 ;
        RECT  18.792 2.151 18.912 19.449 ;
        RECT  16.092 2.151 16.212 19.449 ;
        RECT  13.392 2.151 13.512 19.449 ;
        RECT  10.692 2.151 10.812 19.449 ;
        RECT  7.992 2.151 8.112 19.449 ;
        RECT  5.292 2.151 5.412 19.449 ;
        RECT  2.592 2.151 2.712 19.449 ;
    END
  END VDD
  PIN VSS
    DIRECTION INOUT ;
    USE GROUND ;
    PORT
      LAYER M5 ;
        RECT  18.6 2.137 18.72 19.463 ;
        RECT  15.9 2.137 16.02 19.463 ;
        RECT  13.2 2.137 13.32 19.463 ;
        RECT  10.5 2.137 10.62 19.463 ;
        RECT  7.8 2.137 7.92 19.463 ;
        RECT  5.1 2.137 5.22 19.463 ;
        RECT  2.4 2.137 2.52 19.463 ;
    END
  END VSS
  OBS
    LAYER RVTN ;
     RECT  2.16 2.16 19.44 2.295 ;
     RECT  2.16 2.565 19.44 2.835 ;
     RECT  2.16 3.105 19.44 3.375 ;
     RECT  2.16 3.645 19.44 3.915 ;
     RECT  2.16 4.185 19.44 4.455 ;
     RECT  2.16 4.725 19.44 4.995 ;
     RECT  2.16 5.265 19.44 5.535 ;
     RECT  2.16 5.805 19.44 6.075 ;
     RECT  2.16 6.345 19.44 6.615 ;
     RECT  2.16 6.885 19.44 7.155 ;
     RECT  2.16 7.425 19.44 7.695 ;
     RECT  2.16 7.965 19.44 8.235 ;
     RECT  2.16 8.505 19.44 8.775 ;
     RECT  2.16 9.045 19.44 9.315 ;
     RECT  2.16 9.585 19.44 9.855 ;
     RECT  2.16 10.125 19.44 10.395 ;
     RECT  2.16 10.665 19.44 10.935 ;
     RECT  2.16 11.205 19.44 11.475 ;
     RECT  2.16 11.745 19.44 12.015 ;
     RECT  2.16 12.285 19.44 12.555 ;
     RECT  2.16 12.825 19.44 13.095 ;
     RECT  2.16 13.365 19.44 13.635 ;
     RECT  2.16 13.905 19.44 14.175 ;
     RECT  2.16 14.445 19.44 14.715 ;
     RECT  2.16 14.985 19.44 15.255 ;
     RECT  2.16 15.525 19.44 15.795 ;
     RECT  2.16 16.065 19.44 16.335 ;
     RECT  2.16 16.605 19.44 16.875 ;
     RECT  2.16 17.145 19.44 17.415 ;
     RECT  2.16 17.685 19.44 17.955 ;
     RECT  2.16 18.225 19.44 18.495 ;
     RECT  2.16 18.765 19.44 19.035 ;
     RECT  2.16 19.305 19.44 19.44 ;
    LAYER RVTP ;
     RECT  2.16 2.295 19.44 2.565 ;
     RECT  2.16 2.835 19.44 3.105 ;
     RECT  2.16 3.375 19.44 3.645 ;
     RECT  2.16 3.915 19.44 4.185 ;
     RECT  2.16 4.455 19.44 4.725 ;
     RECT  2.16 4.995 19.44 5.265 ;
     RECT  2.16 5.535 19.44 5.805 ;
     RECT  2.16 6.075 19.44 6.345 ;
     RECT  2.16 6.615 19.44 6.885 ;
     RECT  2.16 7.155 19.44 7.425 ;
     RECT  2.16 7.695 19.44 7.965 ;
     RECT  2.16 8.235 19.44 8.505 ;
     RECT  2.16 8.775 19.44 9.045 ;
     RECT  2.16 9.315 19.44 9.585 ;
     RECT  2.16 9.855 19.44 10.125 ;
     RECT  2.16 10.395 19.44 10.665 ;
     RECT  2.16 10.935 19.44 11.205 ;
     RECT  2.16 11.475 19.44 11.745 ;
     RECT  2.16 12.015 19.44 12.285 ;
     RECT  2.16 12.555 19.44 12.825 ;
     RECT  2.16 13.095 19.44 13.365 ;
     RECT  2.16 13.635 19.44 13.905 ;
     RECT  2.16 14.175 19.44 14.445 ;
     RECT  2.16 14.715 19.44 14.985 ;
     RECT  2.16 15.255 19.44 15.525 ;
     RECT  2.16 15.795 19.44 16.065 ;
     RECT  2.16 16.335 19.44 16.605 ;
     RECT  2.16 16.875 19.44 17.145 ;
     RECT  2.16 17.415 19.44 17.685 ;
     RECT  2.16 17.955 19.44 18.225 ;
     RECT  2.16 18.495 19.44 18.765 ;
     RECT  2.16 19.035 19.44 19.305 ;
    LAYER M1 ;
     RECT  2.16 2.151 19.44 19.449 ;
    LAYER M2 ;
     RECT  0.103 17.082 0.139 17.1 ;
     RECT  0.175 8.982 0.383 9 ;
     RECT  0.103 3.312 0.499 3.978 ;
     RECT  0.499 3.15 0.823 3.978 ;
     RECT  0.211 5.004 0.823 5.022 ;
     RECT  0.535 12.366 1.399 12.384 ;
     RECT  1.147 15.462 1.723 15.48 ;
     RECT  0.823 3.15 2.16 5.022 ;
     RECT  1.399 12.33 2.16 12.384 ;
     RECT  1.723 15.462 2.16 15.588 ;
     RECT  0.139 16.848 2.16 17.1 ;
     RECT  2.16 2.151 3.451 19.449 ;
     RECT  3.451 1.962 5.863 19.449 ;
     RECT  5.863 1.881 8.663 19.449 ;
     RECT  8.663 2.07 14.315 19.449 ;
     RECT  14.315 2.151 19.44 19.449 ;
     RECT  19.44 6.084 19.931 9.684 ;
     RECT  19.44 10.638 19.931 10.764 ;
     RECT  19.44 3.276 19.967 5.184 ;
     RECT  19.931 8.244 20.003 9.684 ;
     RECT  19.931 6.084 20.435 7.452 ;
     RECT  19.967 3.726 20.471 5.184 ;
     RECT  20.471 3.726 20.507 4.914 ;
     RECT  20.435 7.398 20.507 7.452 ;
     RECT  20.003 9.324 20.507 9.684 ;
     RECT  19.44 13.608 20.507 16.434 ;
     RECT  20.003 8.244 20.543 8.532 ;
     RECT  19.44 12.33 20.543 12.654 ;
     RECT  19.44 17.19 20.543 18.522 ;
     RECT  20.507 7.434 20.579 7.452 ;
     RECT  20.543 17.496 20.615 17.748 ;
     RECT  20.543 18.504 21.271 18.522 ;
     RECT  19.931 10.746 21.343 10.764 ;
     RECT  20.615 17.496 21.343 17.514 ;
     RECT  20.435 6.084 21.407 6.642 ;
     RECT  20.543 8.316 21.415 8.532 ;
     RECT  20.507 9.396 21.415 9.414 ;
     RECT  21.343 10.674 21.415 10.764 ;
     RECT  21.343 11.601 21.415 11.619 ;
     RECT  20.507 14.688 21.415 14.706 ;
     RECT  20.507 15.534 21.415 16.434 ;
     RECT  21.271 18.504 21.415 18.792 ;
     RECT  21.415 14.688 21.479 16.434 ;
     RECT  21.343 17.424 21.479 17.514 ;
     RECT  20.507 3.888 21.515 3.906 ;
     RECT  21.407 6.246 21.515 6.642 ;
     RECT  21.415 8.316 21.515 11.619 ;
     RECT  20.543 12.636 21.515 12.654 ;
     RECT  20.507 13.608 21.515 13.626 ;
     RECT  21.479 14.688 21.515 16.362 ;
     RECT  21.479 17.496 21.515 17.514 ;
     RECT  21.415 18.504 21.515 18.864 ;
     RECT  21.515 6.246 21.587 6.264 ;
     RECT  21.515 9.711 21.587 9.729 ;
    LAYER M3 ;
     RECT  8.532 1.723 8.55 1.876 ;
     RECT  3.456 1.957 3.474 2.029 ;
     RECT  4.968 1.957 5.058 2.029 ;
     RECT  5.868 1.876 5.886 2.029 ;
     RECT  6.624 1.957 6.642 2.029 ;
     RECT  4.824 2.029 5.886 2.065 ;
     RECT  6.624 2.029 6.966 2.065 ;
     RECT  4.824 2.065 6.966 2.101 ;
     RECT  4.32 2.101 7.794 2.143 ;
     RECT  8.532 1.876 8.658 2.143 ;
     RECT  2.415 2.143 2.505 2.191 ;
     RECT  3.456 2.029 3.582 2.191 ;
     RECT  4.32 2.143 8.658 2.191 ;
     RECT  10.515 2.143 10.605 2.299 ;
     RECT  2.34 2.191 8.658 2.335 ;
     RECT  10.152 2.299 10.605 2.335 ;
     RECT  2.34 2.335 10.605 2.413 ;
     RECT  13.215 2.143 13.305 2.413 ;
     RECT  15.915 2.143 16.005 2.413 ;
     RECT  18.615 2.143 18.705 2.413 ;
     RECT  2.34 2.413 10.797 2.443 ;
     RECT  13.215 2.413 13.497 2.497 ;
     RECT  18.615 2.413 18.897 2.605 ;
     RECT  2.304 2.443 10.797 2.635 ;
     RECT  2.268 2.635 10.797 2.731 ;
     RECT  2.232 2.731 10.797 2.795 ;
     RECT  0.828 2.827 0.846 2.923 ;
     RECT  0.324 2.923 0.846 3.019 ;
     RECT  2.268 2.795 10.797 3.109 ;
     RECT  2.268 3.109 10.818 3.245 ;
     RECT  0.144 3.019 0.846 3.307 ;
     RECT  2.304 3.245 10.818 3.451 ;
     RECT  14.292 2.065 14.31 3.541 ;
     RECT  2.304 3.451 10.854 3.685 ;
     RECT  11.664 3.541 11.682 3.685 ;
     RECT  17.136 3.181 17.154 3.685 ;
     RECT  18.036 2.605 18.897 3.685 ;
     RECT  19.944 3.271 19.962 3.721 ;
     RECT  14.292 3.541 14.85 3.749 ;
     RECT  19.944 3.721 20.502 3.979 ;
     RECT  21.492 3.883 21.51 4.109 ;
     RECT  19.908 3.979 20.502 4.217 ;
     RECT  0.108 3.307 0.846 4.397 ;
     RECT  0.144 4.397 0.846 4.523 ;
     RECT  20.448 4.217 20.502 4.919 ;
     RECT  14.292 3.749 14.31 4.999 ;
     RECT  14.292 4.999 14.994 5.071 ;
     RECT  15.915 2.413 16.197 5.071 ;
     RECT  20.448 4.919 20.466 5.189 ;
     RECT  14.292 5.071 16.197 5.197 ;
     RECT  17.136 3.685 19.098 5.197 ;
     RECT  14.292 5.197 19.098 5.261 ;
     RECT  2.304 3.685 11.682 5.419 ;
     RECT  0.144 4.523 0.234 5.707 ;
     RECT  12.564 2.497 13.497 5.845 ;
     RECT  14.292 5.261 18.897 5.845 ;
     RECT  12.564 5.845 18.897 6.007 ;
     RECT  0.144 5.707 0.342 6.125 ;
     RECT  0.216 6.125 0.234 6.221 ;
     RECT  21.384 6.079 21.402 6.241 ;
     RECT  2.268 5.419 11.682 6.269 ;
     RECT  12.564 6.007 19.278 6.269 ;
     RECT  15.915 6.269 19.278 6.313 ;
     RECT  15.915 6.313 19.35 6.691 ;
     RECT  15.915 6.691 19.422 6.889 ;
     RECT  20.196 6.151 20.214 6.889 ;
     RECT  2.304 6.269 11.682 7.051 ;
     RECT  15.915 6.889 20.214 7.147 ;
     RECT  15.915 7.147 20.43 7.393 ;
     RECT  15.915 7.393 20.502 7.429 ;
     RECT  15.915 7.429 20.574 7.853 ;
     RECT  2.268 7.051 11.682 8.041 ;
     RECT  12.564 6.269 14.994 8.131 ;
     RECT  15.915 7.853 19.35 8.131 ;
     RECT  2.268 8.041 11.718 8.159 ;
     RECT  20.196 7.853 20.574 8.237 ;
     RECT  20.196 8.237 20.538 8.429 ;
     RECT  12.564 8.131 19.35 8.581 ;
     RECT  20.196 8.429 20.214 8.581 ;
     RECT  0.144 7.819 0.162 8.875 ;
     RECT  2.268 8.159 11.682 8.941 ;
     RECT  12.564 8.581 20.214 8.941 ;
     RECT  0.144 8.875 0.342 8.977 ;
     RECT  0.144 8.977 0.378 9.101 ;
     RECT  2.268 8.941 20.214 9.101 ;
     RECT  20.196 9.101 20.214 9.163 ;
     RECT  20.196 9.163 20.502 9.293 ;
     RECT  20.484 9.293 20.502 9.689 ;
     RECT  21.384 6.241 21.582 9.734 ;
     RECT  2.268 9.101 19.35 9.739 ;
     RECT  2.232 9.739 19.35 9.851 ;
     RECT  12.564 9.851 19.35 9.859 ;
     RECT  0.144 9.101 0.162 9.883 ;
     RECT  2.232 9.851 11.718 9.887 ;
     RECT  0.144 9.883 0.234 10.027 ;
     RECT  2.268 9.887 11.718 10.085 ;
     RECT  0.144 10.027 0.342 10.109 ;
     RECT  0.216 10.109 0.342 10.157 ;
     RECT  21.384 9.734 21.51 10.603 ;
     RECT  12.564 9.859 19.422 10.633 ;
     RECT  21.276 10.603 21.51 10.733 ;
     RECT  12.564 10.633 19.926 11.021 ;
     RECT  2.304 10.085 11.718 11.323 ;
     RECT  2.196 11.323 11.718 11.371 ;
     RECT  2.196 11.371 11.754 11.443 ;
     RECT  21.384 10.733 21.51 11.515 ;
     RECT  2.196 11.443 11.826 11.705 ;
     RECT  2.304 11.705 11.826 11.713 ;
     RECT  12.564 11.021 19.35 11.713 ;
     RECT  21.348 11.515 21.51 11.789 ;
     RECT  21.348 11.789 21.438 11.851 ;
     RECT  0.324 10.157 0.342 11.981 ;
     RECT  21.312 11.851 21.438 11.981 ;
     RECT  2.304 11.713 19.35 12.019 ;
     RECT  2.304 12.019 19.422 12.173 ;
     RECT  2.304 12.173 19.278 12.209 ;
     RECT  1.404 10.219 1.422 12.353 ;
     RECT  2.304 12.209 11.718 12.427 ;
     RECT  20.52 12.325 20.538 12.461 ;
     RECT  2.268 12.427 11.718 12.479 ;
     RECT  21.42 11.981 21.438 12.523 ;
     RECT  2.268 12.479 11.682 12.587 ;
     RECT  0.54 12.361 0.558 12.653 ;
     RECT  21.42 12.523 21.51 12.659 ;
     RECT  21.42 12.659 21.438 12.715 ;
     RECT  12.564 12.209 19.278 12.901 ;
     RECT  0.144 12.859 0.162 13.037 ;
     RECT  21.348 12.715 21.438 13.085 ;
     RECT  21.42 13.085 21.438 13.373 ;
     RECT  12.564 12.901 19.314 13.405 ;
     RECT  2.304 12.587 11.682 13.441 ;
     RECT  2.268 13.441 11.682 13.531 ;
     RECT  12.492 13.405 19.314 13.531 ;
     RECT  2.268 13.531 19.314 13.613 ;
     RECT  21.492 13.579 21.51 13.631 ;
     RECT  2.268 13.613 12.222 13.661 ;
     RECT  13.068 13.613 19.314 13.771 ;
     RECT  20.448 13.675 20.466 13.963 ;
     RECT  1.152 13.579 1.17 14.059 ;
     RECT  2.268 13.661 11.682 14.059 ;
     RECT  13.068 13.771 19.386 14.059 ;
     RECT  20.448 13.963 20.502 14.059 ;
     RECT  13.068 14.059 20.502 14.207 ;
     RECT  13.215 14.207 20.502 14.381 ;
     RECT  0.324 14.443 0.342 14.539 ;
     RECT  21.42 14.443 21.438 14.539 ;
     RECT  19.908 14.381 20.502 14.549 ;
     RECT  0.216 14.539 0.342 14.635 ;
     RECT  0.108 14.635 0.342 14.669 ;
     RECT  0.108 14.669 0.234 14.717 ;
     RECT  0.108 14.717 0.126 14.765 ;
     RECT  13.215 14.381 19.134 14.989 ;
     RECT  13.104 14.989 19.134 15.323 ;
     RECT  14.652 15.323 19.134 15.449 ;
     RECT  1.152 14.059 11.682 15.485 ;
     RECT  1.728 15.485 11.682 15.565 ;
     RECT  1.728 15.565 12.006 15.593 ;
     RECT  20.484 14.549 20.502 15.601 ;
     RECT  19.944 15.601 20.502 15.725 ;
     RECT  20.484 15.725 20.502 15.763 ;
     RECT  20.484 15.763 20.538 15.989 ;
     RECT  20.52 15.989 20.538 16.013 ;
     RECT  21.42 14.539 21.51 16.027 ;
     RECT  21.276 16.027 21.51 16.363 ;
     RECT  13.104 15.323 13.497 16.397 ;
     RECT  21.24 16.363 21.51 16.493 ;
     RECT  13.176 16.397 13.497 16.541 ;
     RECT  14.652 15.449 19.062 16.681 ;
     RECT  2.415 15.593 12.006 16.709 ;
     RECT  13.215 16.541 13.497 16.795 ;
     RECT  11.736 16.709 12.006 16.907 ;
     RECT  2.415 16.709 10.962 16.915 ;
     RECT  13.215 16.795 13.59 16.973 ;
     RECT  14.652 16.681 19.098 17.069 ;
     RECT  0.144 16.843 0.162 17.077 ;
     RECT  0.108 17.077 0.162 17.165 ;
     RECT  20.52 17.185 20.538 17.227 ;
     RECT  21.276 16.493 21.51 17.227 ;
     RECT  2.304 16.915 10.962 17.323 ;
     RECT  14.832 17.069 19.098 17.339 ;
     RECT  2.268 17.323 10.962 17.447 ;
     RECT  0.144 17.165 0.162 17.453 ;
     RECT  20.52 17.227 21.51 17.519 ;
     RECT  15.228 17.339 19.098 17.581 ;
     RECT  2.34 17.447 10.962 17.609 ;
     RECT  2.34 17.609 10.854 17.645 ;
     RECT  13.215 16.973 13.497 17.761 ;
     RECT  20.52 17.519 21.294 17.837 ;
     RECT  13.104 17.761 13.497 17.951 ;
     RECT  2.415 17.645 10.854 18.059 ;
     RECT  20.592 17.837 21.294 18.125 ;
     RECT  4.212 18.059 10.854 18.149 ;
     RECT  11.988 16.907 12.006 18.149 ;
     RECT  6.732 18.149 10.854 18.173 ;
     RECT  2.415 18.059 3.15 18.185 ;
     RECT  4.356 18.149 5.49 18.185 ;
     RECT  15.228 17.581 19.134 18.193 ;
     RECT  4.932 18.185 5.49 18.221 ;
     RECT  6.768 18.173 10.854 18.221 ;
     RECT  14.832 18.193 19.134 18.293 ;
     RECT  21.24 18.125 21.294 18.379 ;
     RECT  6.768 18.221 9.162 18.419 ;
     RECT  14.832 18.293 19.062 18.419 ;
     RECT  6.84 18.419 9.162 18.461 ;
     RECT  21.24 18.379 21.33 18.475 ;
     RECT  21.24 18.475 21.51 18.509 ;
     RECT  14.832 18.419 18.897 18.599 ;
     RECT  9.936 18.221 10.854 18.689 ;
     RECT  10.515 18.689 10.854 18.733 ;
     RECT  7.815 18.461 9.162 18.761 ;
     RECT  21.276 18.509 21.51 18.797 ;
     RECT  10.515 18.733 11.358 18.869 ;
     RECT  21.384 18.797 21.51 18.893 ;
     RECT  21.384 18.893 21.402 19.085 ;
     RECT  7.815 18.761 8.622 19.103 ;
     RECT  2.415 18.185 2.697 19.187 ;
     RECT  5.115 18.221 5.397 19.187 ;
     RECT  7.815 19.103 8.097 19.187 ;
     RECT  10.515 18.869 10.797 19.187 ;
     RECT  14.904 18.599 18.897 19.187 ;
     RECT  13.176 17.951 13.497 19.201 ;
     RECT  13.176 19.201 13.554 19.229 ;
     RECT  14.904 19.187 18.705 19.229 ;
     RECT  6.84 18.461 6.858 19.277 ;
     RECT  15.12 19.229 18.705 19.277 ;
     RECT  15.12 19.277 17.586 19.301 ;
     RECT  13.215 19.229 13.554 19.337 ;
     RECT  15.12 19.301 16.005 19.373 ;
     RECT  17.208 19.301 17.298 19.373 ;
     RECT  18.324 19.277 18.705 19.373 ;
     RECT  15.264 19.373 16.005 19.409 ;
     RECT  2.415 19.187 2.505 19.457 ;
     RECT  5.115 19.187 5.205 19.457 ;
     RECT  7.815 19.187 7.905 19.457 ;
     RECT  10.515 19.187 10.605 19.457 ;
     RECT  13.215 19.337 13.305 19.457 ;
     RECT  15.915 19.409 16.005 19.457 ;
     RECT  18.615 19.373 18.705 19.457 ;
    LAYER M4 ;
     RECT  0.06 2.448 0.097 14.664 ;
     RECT  0.097 2.448 2.408 14.76 ;
     RECT  0.06 17.04 2.408 17.736 ;
     RECT  2.408 2.148 2.512 19.452 ;
     RECT  2.512 2.256 2.704 19.182 ;
     RECT  2.704 17.616 2.765 17.64 ;
     RECT  2.704 2.256 2.945 14.664 ;
     RECT  2.945 13.536 2.981 14.664 ;
     RECT  2.945 2.256 3.017 11.976 ;
     RECT  3.017 2.256 3.341 11.784 ;
     RECT  3.341 2.256 3.347 5.256 ;
     RECT  3.347 2.544 3.557 5.256 ;
     RECT  2.981 13.536 3.949 14.376 ;
     RECT  2.704 15.984 3.949 16.008 ;
     RECT  3.341 6.24 4.165 11.784 ;
     RECT  3.949 13.008 4.165 16.008 ;
     RECT  4.165 6.24 4.201 16.008 ;
     RECT  3.557 2.784 4.381 5.256 ;
     RECT  4.201 6.24 4.381 17.16 ;
     RECT  4.381 2.784 4.453 17.16 ;
     RECT  4.309 18.144 4.453 18.168 ;
     RECT  4.453 2.784 5.108 18.168 ;
     RECT  5.108 2.148 5.212 19.452 ;
     RECT  5.212 2.418 5.404 19.182 ;
     RECT  5.404 2.496 6.323 17.304 ;
     RECT  6.323 2.544 6.433 17.304 ;
     RECT  6.433 2.544 6.721 17.4 ;
     RECT  6.721 2.544 7.081 18.168 ;
     RECT  6.829 19.248 7.081 19.272 ;
     RECT  7.081 2.544 7.808 19.272 ;
     RECT  7.808 2.148 7.912 19.452 ;
     RECT  7.912 2.148 8.104 19.272 ;
     RECT  8.104 2.148 8.237 13.32 ;
     RECT  8.237 2.148 8.477 13.128 ;
     RECT  8.477 1.728 8.561 13.128 ;
     RECT  8.561 2.592 9.209 13.128 ;
     RECT  9.209 4.224 9.317 13.128 ;
     RECT  9.317 6.672 9.389 13.128 ;
     RECT  9.317 4.224 9.497 5.592 ;
     RECT  9.389 7.392 9.497 13.128 ;
     RECT  8.104 14.64 9.817 19.272 ;
     RECT  9.209 2.592 10.508 3.144 ;
     RECT  9.497 4.224 10.508 4.248 ;
     RECT  9.497 5.568 10.508 5.592 ;
     RECT  9.497 7.536 10.508 13.128 ;
     RECT  9.817 14.112 10.508 19.272 ;
     RECT  10.508 2.148 10.612 19.452 ;
     RECT  10.612 2.418 10.804 19.272 ;
     RECT  10.804 8.16 13.208 10.68 ;
     RECT  10.804 11.664 13.208 19.272 ;
     RECT  13.208 2.148 13.312 19.452 ;
     RECT  13.312 2.418 13.504 19.272 ;
     RECT  13.504 8.16 15.109 19.272 ;
     RECT  15.109 8.16 15.908 19.368 ;
     RECT  15.908 2.148 16.012 19.452 ;
     RECT  16.012 2.418 16.204 19.368 ;
     RECT  16.204 7.584 18.241 19.368 ;
     RECT  18.241 7.344 18.421 19.368 ;
     RECT  18.421 6.912 18.608 19.368 ;
     RECT  18.608 2.148 18.712 19.452 ;
     RECT  18.712 2.418 18.904 19.182 ;
     RECT  19.897 3.984 19.933 4.008 ;
     RECT  19.933 3.888 20.437 4.008 ;
     RECT  20.437 3.888 20.473 4.392 ;
     RECT  18.904 6.864 21.373 18.984 ;
     RECT  20.473 3.792 21.564 4.488 ;
     RECT  21.373 6.864 21.564 19.08 ;
    LAYER M5 ;
     RECT  8.4 0.016 8.52 1.763 ;
     RECT  8.4 1.763 8.424 2.137 ;
     RECT  2.4 2.137 2.52 2.151 ;
     RECT  5.1 2.137 5.22 2.151 ;
     RECT  10.5 2.137 10.62 2.151 ;
     RECT  13.2 2.137 13.32 2.151 ;
     RECT  15.9 2.137 16.02 2.151 ;
     RECT  18.6 2.137 18.72 2.151 ;
     RECT  2.4 2.151 2.712 2.245 ;
     RECT  5.1 2.151 5.412 2.485 ;
     RECT  5.1 2.485 6.312 2.533 ;
     RECT  7.8 2.137 8.424 2.533 ;
     RECT  2.4 2.245 3.336 2.915 ;
     RECT  2.4 2.915 2.712 3.685 ;
     RECT  2.304 3.685 2.712 3.827 ;
     RECT  5.1 2.533 8.424 4.019 ;
     RECT  5.1 4.019 6.312 4.067 ;
     RECT  5.1 4.067 6.168 4.117 ;
     RECT  7.68 4.019 8.424 5.461 ;
     RECT  2.4 3.827 2.712 5.557 ;
     RECT  0.144 5.125 0.168 5.797 ;
     RECT  0.144 5.797 0.216 6.179 ;
     RECT  2.4 5.557 2.856 6.755 ;
     RECT  0.144 6.179 0.168 6.851 ;
     RECT  4.848 4.117 6.168 7.621 ;
     RECT  7.536 5.461 8.424 8.195 ;
     RECT  4.56 7.621 6.168 8.485 ;
     RECT  7.8 8.195 8.424 8.531 ;
     RECT  4.56 8.485 6.264 9.589 ;
     RECT  4.56 9.589 6.36 10.165 ;
     RECT  15.9 2.151 16.212 10.405 ;
     RECT  15.9 10.405 17.112 10.595 ;
     RECT  4.512 10.165 6.36 10.787 ;
     RECT  4.512 10.787 6.168 11.507 ;
     RECT  5.1 11.507 6.168 11.797 ;
     RECT  5.1 11.797 6.408 11.893 ;
     RECT  7.8 8.531 8.232 11.939 ;
     RECT  0.144 10.357 0.168 11.987 ;
     RECT  21.408 11.797 21.432 11.987 ;
     RECT  5.1 11.893 6.552 12.901 ;
     RECT  4.416 12.901 6.552 13.139 ;
     RECT  6.384 13.139 6.552 13.141 ;
     RECT  7.8 11.939 8.112 13.141 ;
     RECT  4.416 13.139 5.412 14.101 ;
     RECT  6.384 13.141 8.112 14.101 ;
     RECT  4.416 14.101 8.112 14.291 ;
     RECT  4.416 14.291 6.408 14.341 ;
     RECT  4.08 14.341 6.408 14.531 ;
     RECT  6.384 14.531 6.408 15.349 ;
     RECT  7.392 14.291 8.112 15.349 ;
     RECT  4.08 14.531 5.412 15.443 ;
     RECT  6.384 15.349 8.232 15.443 ;
     RECT  4.08 15.443 4.104 15.827 ;
     RECT  5.1 15.443 5.412 16.501 ;
     RECT  15.9 10.595 16.212 16.501 ;
     RECT  15.9 16.501 17.112 16.739 ;
     RECT  21.408 16.837 21.432 16.933 ;
     RECT  20.496 16.933 21.432 17.123 ;
     RECT  20.496 17.123 20.52 17.219 ;
     RECT  7.152 15.443 8.232 17.411 ;
     RECT  7.8 17.411 8.232 17.507 ;
     RECT  15.9 16.739 17.016 17.699 ;
     RECT  4.32 16.501 5.412 18.179 ;
     RECT  2.4 6.755 2.712 19.449 ;
     RECT  5.1 18.179 5.412 19.449 ;
     RECT  7.8 17.507 8.112 19.449 ;
     RECT  10.5 2.151 10.812 19.449 ;
     RECT  13.2 2.151 13.512 19.449 ;
     RECT  15.9 17.699 16.212 19.449 ;
     RECT  18.6 2.151 18.912 19.449 ;
     RECT  2.4 19.449 2.52 19.463 ;
     RECT  5.1 19.449 5.22 19.463 ;
     RECT  7.8 19.449 7.92 19.463 ;
     RECT  10.5 19.449 10.62 19.463 ;
     RECT  13.2 19.449 13.32 19.463 ;
     RECT  15.9 19.449 16.02 19.463 ;
     RECT  18.6 19.449 18.72 19.463 ;
  END
END hbfd_rly_136_WE
END LIBRARY
